# Generated by FakeRAM 2.0
VERSION 5.7 ;
BUSBITCHARS "[]" ;
PROPERTYDEFINITIONS
  MACRO width INTEGER ;
  MACRO depth INTEGER ;
  MACRO banks INTEGER ;
END PROPERTYDEFINITIONS
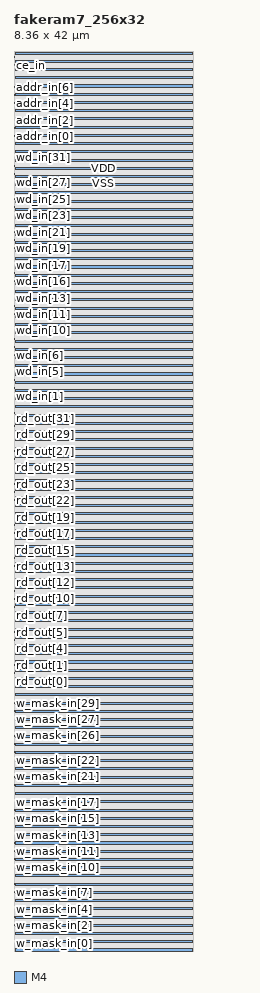
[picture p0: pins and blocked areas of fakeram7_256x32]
MACRO fakeram7_256x32
  PROPERTY width 32 ;
  PROPERTY depth 256 ;
  PROPERTY banks 2 ;
  FOREIGN fakeram7_256x32 0 0 ;
  SYMMETRY X Y R90 ;
  SIZE 8.360 BY 42.000 ;
  CLASS BLOCK ;
  PIN w_mask_in[0]
    DIRECTION INPUT ;
    USE SIGNAL ;
    SHAPE ABUTMENT ;
    PORT
      LAYER M4 ;
      RECT 0.000 0.048 0.024 0.072 ;
    END
  END w_mask_in[0]
  PIN w_mask_in[1]
    DIRECTION INPUT ;
    USE SIGNAL ;
    SHAPE ABUTMENT ;
    PORT
      LAYER M4 ;
      RECT 0.000 0.432 0.024 0.456 ;
    END
  END w_mask_in[1]
  PIN w_mask_in[2]
    DIRECTION INPUT ;
    USE SIGNAL ;
    SHAPE ABUTMENT ;
    PORT
      LAYER M4 ;
      RECT 0.000 0.816 0.024 0.840 ;
    END
  END w_mask_in[2]
  PIN w_mask_in[3]
    DIRECTION INPUT ;
    USE SIGNAL ;
    SHAPE ABUTMENT ;
    PORT
      LAYER M4 ;
      RECT 0.000 1.200 0.024 1.224 ;
    END
  END w_mask_in[3]
  PIN w_mask_in[4]
    DIRECTION INPUT ;
    USE SIGNAL ;
    SHAPE ABUTMENT ;
    PORT
      LAYER M4 ;
      RECT 0.000 1.584 0.024 1.608 ;
    END
  END w_mask_in[4]
  PIN w_mask_in[5]
    DIRECTION INPUT ;
    USE SIGNAL ;
    SHAPE ABUTMENT ;
    PORT
      LAYER M4 ;
      RECT 0.000 1.968 0.024 1.992 ;
    END
  END w_mask_in[5]
  PIN w_mask_in[6]
    DIRECTION INPUT ;
    USE SIGNAL ;
    SHAPE ABUTMENT ;
    PORT
      LAYER M4 ;
      RECT 0.000 2.352 0.024 2.376 ;
    END
  END w_mask_in[6]
  PIN w_mask_in[7]
    DIRECTION INPUT ;
    USE SIGNAL ;
    SHAPE ABUTMENT ;
    PORT
      LAYER M4 ;
      RECT 0.000 2.736 0.024 2.760 ;
    END
  END w_mask_in[7]
  PIN w_mask_in[8]
    DIRECTION INPUT ;
    USE SIGNAL ;
    SHAPE ABUTMENT ;
    PORT
      LAYER M4 ;
      RECT 0.000 3.120 0.024 3.144 ;
    END
  END w_mask_in[8]
  PIN w_mask_in[9]
    DIRECTION INPUT ;
    USE SIGNAL ;
    SHAPE ABUTMENT ;
    PORT
      LAYER M4 ;
      RECT 0.000 3.504 0.024 3.528 ;
    END
  END w_mask_in[9]
  PIN w_mask_in[10]
    DIRECTION INPUT ;
    USE SIGNAL ;
    SHAPE ABUTMENT ;
    PORT
      LAYER M4 ;
      RECT 0.000 3.888 0.024 3.912 ;
    END
  END w_mask_in[10]
  PIN w_mask_in[11]
    DIRECTION INPUT ;
    USE SIGNAL ;
    SHAPE ABUTMENT ;
    PORT
      LAYER M4 ;
      RECT 0.000 4.272 0.024 4.296 ;
    END
  END w_mask_in[11]
  PIN w_mask_in[12]
    DIRECTION INPUT ;
    USE SIGNAL ;
    SHAPE ABUTMENT ;
    PORT
      LAYER M4 ;
      RECT 0.000 4.656 0.024 4.680 ;
    END
  END w_mask_in[12]
  PIN w_mask_in[13]
    DIRECTION INPUT ;
    USE SIGNAL ;
    SHAPE ABUTMENT ;
    PORT
      LAYER M4 ;
      RECT 0.000 5.040 0.024 5.064 ;
    END
  END w_mask_in[13]
  PIN w_mask_in[14]
    DIRECTION INPUT ;
    USE SIGNAL ;
    SHAPE ABUTMENT ;
    PORT
      LAYER M4 ;
      RECT 0.000 5.424 0.024 5.448 ;
    END
  END w_mask_in[14]
  PIN w_mask_in[15]
    DIRECTION INPUT ;
    USE SIGNAL ;
    SHAPE ABUTMENT ;
    PORT
      LAYER M4 ;
      RECT 0.000 5.808 0.024 5.832 ;
    END
  END w_mask_in[15]
  PIN w_mask_in[16]
    DIRECTION INPUT ;
    USE SIGNAL ;
    SHAPE ABUTMENT ;
    PORT
      LAYER M4 ;
      RECT 0.000 6.192 0.024 6.216 ;
    END
  END w_mask_in[16]
  PIN w_mask_in[17]
    DIRECTION INPUT ;
    USE SIGNAL ;
    SHAPE ABUTMENT ;
    PORT
      LAYER M4 ;
      RECT 0.000 6.576 0.024 6.600 ;
    END
  END w_mask_in[17]
  PIN w_mask_in[18]
    DIRECTION INPUT ;
    USE SIGNAL ;
    SHAPE ABUTMENT ;
    PORT
      LAYER M4 ;
      RECT 0.000 6.960 0.024 6.984 ;
    END
  END w_mask_in[18]
  PIN w_mask_in[19]
    DIRECTION INPUT ;
    USE SIGNAL ;
    SHAPE ABUTMENT ;
    PORT
      LAYER M4 ;
      RECT 0.000 7.344 0.024 7.368 ;
    END
  END w_mask_in[19]
  PIN w_mask_in[20]
    DIRECTION INPUT ;
    USE SIGNAL ;
    SHAPE ABUTMENT ;
    PORT
      LAYER M4 ;
      RECT 0.000 7.728 0.024 7.752 ;
    END
  END w_mask_in[20]
  PIN w_mask_in[21]
    DIRECTION INPUT ;
    USE SIGNAL ;
    SHAPE ABUTMENT ;
    PORT
      LAYER M4 ;
      RECT 0.000 8.112 0.024 8.136 ;
    END
  END w_mask_in[21]
  PIN w_mask_in[22]
    DIRECTION INPUT ;
    USE SIGNAL ;
    SHAPE ABUTMENT ;
    PORT
      LAYER M4 ;
      RECT 0.000 8.496 0.024 8.520 ;
    END
  END w_mask_in[22]
  PIN w_mask_in[23]
    DIRECTION INPUT ;
    USE SIGNAL ;
    SHAPE ABUTMENT ;
    PORT
      LAYER M4 ;
      RECT 0.000 8.880 0.024 8.904 ;
    END
  END w_mask_in[23]
  PIN w_mask_in[24]
    DIRECTION INPUT ;
    USE SIGNAL ;
    SHAPE ABUTMENT ;
    PORT
      LAYER M4 ;
      RECT 0.000 9.264 0.024 9.288 ;
    END
  END w_mask_in[24]
  PIN w_mask_in[25]
    DIRECTION INPUT ;
    USE SIGNAL ;
    SHAPE ABUTMENT ;
    PORT
      LAYER M4 ;
      RECT 0.000 9.648 0.024 9.672 ;
    END
  END w_mask_in[25]
  PIN w_mask_in[26]
    DIRECTION INPUT ;
    USE SIGNAL ;
    SHAPE ABUTMENT ;
    PORT
      LAYER M4 ;
      RECT 0.000 10.032 0.024 10.056 ;
    END
  END w_mask_in[26]
  PIN w_mask_in[27]
    DIRECTION INPUT ;
    USE SIGNAL ;
    SHAPE ABUTMENT ;
    PORT
      LAYER M4 ;
      RECT 0.000 10.416 0.024 10.440 ;
    END
  END w_mask_in[27]
  PIN w_mask_in[28]
    DIRECTION INPUT ;
    USE SIGNAL ;
    SHAPE ABUTMENT ;
    PORT
      LAYER M4 ;
      RECT 0.000 10.800 0.024 10.824 ;
    END
  END w_mask_in[28]
  PIN w_mask_in[29]
    DIRECTION INPUT ;
    USE SIGNAL ;
    SHAPE ABUTMENT ;
    PORT
      LAYER M4 ;
      RECT 0.000 11.184 0.024 11.208 ;
    END
  END w_mask_in[29]
  PIN w_mask_in[30]
    DIRECTION INPUT ;
    USE SIGNAL ;
    SHAPE ABUTMENT ;
    PORT
      LAYER M4 ;
      RECT 0.000 11.568 0.024 11.592 ;
    END
  END w_mask_in[30]
  PIN w_mask_in[31]
    DIRECTION INPUT ;
    USE SIGNAL ;
    SHAPE ABUTMENT ;
    PORT
      LAYER M4 ;
      RECT 0.000 11.952 0.024 11.976 ;
    END
  END w_mask_in[31]
  PIN rd_out[0]
    DIRECTION OUTPUT ;
    USE SIGNAL ;
    SHAPE ABUTMENT ;
    PORT
      LAYER M4 ;
      RECT 0.000 12.576 0.024 12.600 ;
    END
  END rd_out[0]
  PIN rd_out[1]
    DIRECTION OUTPUT ;
    USE SIGNAL ;
    SHAPE ABUTMENT ;
    PORT
      LAYER M4 ;
      RECT 0.000 12.960 0.024 12.984 ;
    END
  END rd_out[1]
  PIN rd_out[2]
    DIRECTION OUTPUT ;
    USE SIGNAL ;
    SHAPE ABUTMENT ;
    PORT
      LAYER M4 ;
      RECT 0.000 13.344 0.024 13.368 ;
    END
  END rd_out[2]
  PIN rd_out[3]
    DIRECTION OUTPUT ;
    USE SIGNAL ;
    SHAPE ABUTMENT ;
    PORT
      LAYER M4 ;
      RECT 0.000 13.728 0.024 13.752 ;
    END
  END rd_out[3]
  PIN rd_out[4]
    DIRECTION OUTPUT ;
    USE SIGNAL ;
    SHAPE ABUTMENT ;
    PORT
      LAYER M4 ;
      RECT 0.000 14.112 0.024 14.136 ;
    END
  END rd_out[4]
  PIN rd_out[5]
    DIRECTION OUTPUT ;
    USE SIGNAL ;
    SHAPE ABUTMENT ;
    PORT
      LAYER M4 ;
      RECT 0.000 14.496 0.024 14.520 ;
    END
  END rd_out[5]
  PIN rd_out[6]
    DIRECTION OUTPUT ;
    USE SIGNAL ;
    SHAPE ABUTMENT ;
    PORT
      LAYER M4 ;
      RECT 0.000 14.880 0.024 14.904 ;
    END
  END rd_out[6]
  PIN rd_out[7]
    DIRECTION OUTPUT ;
    USE SIGNAL ;
    SHAPE ABUTMENT ;
    PORT
      LAYER M4 ;
      RECT 0.000 15.264 0.024 15.288 ;
    END
  END rd_out[7]
  PIN rd_out[8]
    DIRECTION OUTPUT ;
    USE SIGNAL ;
    SHAPE ABUTMENT ;
    PORT
      LAYER M4 ;
      RECT 0.000 15.648 0.024 15.672 ;
    END
  END rd_out[8]
  PIN rd_out[9]
    DIRECTION OUTPUT ;
    USE SIGNAL ;
    SHAPE ABUTMENT ;
    PORT
      LAYER M4 ;
      RECT 0.000 16.032 0.024 16.056 ;
    END
  END rd_out[9]
  PIN rd_out[10]
    DIRECTION OUTPUT ;
    USE SIGNAL ;
    SHAPE ABUTMENT ;
    PORT
      LAYER M4 ;
      RECT 0.000 16.416 0.024 16.440 ;
    END
  END rd_out[10]
  PIN rd_out[11]
    DIRECTION OUTPUT ;
    USE SIGNAL ;
    SHAPE ABUTMENT ;
    PORT
      LAYER M4 ;
      RECT 0.000 16.800 0.024 16.824 ;
    END
  END rd_out[11]
  PIN rd_out[12]
    DIRECTION OUTPUT ;
    USE SIGNAL ;
    SHAPE ABUTMENT ;
    PORT
      LAYER M4 ;
      RECT 0.000 17.184 0.024 17.208 ;
    END
  END rd_out[12]
  PIN rd_out[13]
    DIRECTION OUTPUT ;
    USE SIGNAL ;
    SHAPE ABUTMENT ;
    PORT
      LAYER M4 ;
      RECT 0.000 17.568 0.024 17.592 ;
    END
  END rd_out[13]
  PIN rd_out[14]
    DIRECTION OUTPUT ;
    USE SIGNAL ;
    SHAPE ABUTMENT ;
    PORT
      LAYER M4 ;
      RECT 0.000 17.952 0.024 17.976 ;
    END
  END rd_out[14]
  PIN rd_out[15]
    DIRECTION OUTPUT ;
    USE SIGNAL ;
    SHAPE ABUTMENT ;
    PORT
      LAYER M4 ;
      RECT 0.000 18.336 0.024 18.360 ;
    END
  END rd_out[15]
  PIN rd_out[16]
    DIRECTION OUTPUT ;
    USE SIGNAL ;
    SHAPE ABUTMENT ;
    PORT
      LAYER M4 ;
      RECT 0.000 18.720 0.024 18.744 ;
    END
  END rd_out[16]
  PIN rd_out[17]
    DIRECTION OUTPUT ;
    USE SIGNAL ;
    SHAPE ABUTMENT ;
    PORT
      LAYER M4 ;
      RECT 0.000 19.104 0.024 19.128 ;
    END
  END rd_out[17]
  PIN rd_out[18]
    DIRECTION OUTPUT ;
    USE SIGNAL ;
    SHAPE ABUTMENT ;
    PORT
      LAYER M4 ;
      RECT 0.000 19.488 0.024 19.512 ;
    END
  END rd_out[18]
  PIN rd_out[19]
    DIRECTION OUTPUT ;
    USE SIGNAL ;
    SHAPE ABUTMENT ;
    PORT
      LAYER M4 ;
      RECT 0.000 19.872 0.024 19.896 ;
    END
  END rd_out[19]
  PIN rd_out[20]
    DIRECTION OUTPUT ;
    USE SIGNAL ;
    SHAPE ABUTMENT ;
    PORT
      LAYER M4 ;
      RECT 0.000 20.256 0.024 20.280 ;
    END
  END rd_out[20]
  PIN rd_out[21]
    DIRECTION OUTPUT ;
    USE SIGNAL ;
    SHAPE ABUTMENT ;
    PORT
      LAYER M4 ;
      RECT 0.000 20.640 0.024 20.664 ;
    END
  END rd_out[21]
  PIN rd_out[22]
    DIRECTION OUTPUT ;
    USE SIGNAL ;
    SHAPE ABUTMENT ;
    PORT
      LAYER M4 ;
      RECT 0.000 21.024 0.024 21.048 ;
    END
  END rd_out[22]
  PIN rd_out[23]
    DIRECTION OUTPUT ;
    USE SIGNAL ;
    SHAPE ABUTMENT ;
    PORT
      LAYER M4 ;
      RECT 0.000 21.408 0.024 21.432 ;
    END
  END rd_out[23]
  PIN rd_out[24]
    DIRECTION OUTPUT ;
    USE SIGNAL ;
    SHAPE ABUTMENT ;
    PORT
      LAYER M4 ;
      RECT 0.000 21.792 0.024 21.816 ;
    END
  END rd_out[24]
  PIN rd_out[25]
    DIRECTION OUTPUT ;
    USE SIGNAL ;
    SHAPE ABUTMENT ;
    PORT
      LAYER M4 ;
      RECT 0.000 22.176 0.024 22.200 ;
    END
  END rd_out[25]
  PIN rd_out[26]
    DIRECTION OUTPUT ;
    USE SIGNAL ;
    SHAPE ABUTMENT ;
    PORT
      LAYER M4 ;
      RECT 0.000 22.560 0.024 22.584 ;
    END
  END rd_out[26]
  PIN rd_out[27]
    DIRECTION OUTPUT ;
    USE SIGNAL ;
    SHAPE ABUTMENT ;
    PORT
      LAYER M4 ;
      RECT 0.000 22.944 0.024 22.968 ;
    END
  END rd_out[27]
  PIN rd_out[28]
    DIRECTION OUTPUT ;
    USE SIGNAL ;
    SHAPE ABUTMENT ;
    PORT
      LAYER M4 ;
      RECT 0.000 23.328 0.024 23.352 ;
    END
  END rd_out[28]
  PIN rd_out[29]
    DIRECTION OUTPUT ;
    USE SIGNAL ;
    SHAPE ABUTMENT ;
    PORT
      LAYER M4 ;
      RECT 0.000 23.712 0.024 23.736 ;
    END
  END rd_out[29]
  PIN rd_out[30]
    DIRECTION OUTPUT ;
    USE SIGNAL ;
    SHAPE ABUTMENT ;
    PORT
      LAYER M4 ;
      RECT 0.000 24.096 0.024 24.120 ;
    END
  END rd_out[30]
  PIN rd_out[31]
    DIRECTION OUTPUT ;
    USE SIGNAL ;
    SHAPE ABUTMENT ;
    PORT
      LAYER M4 ;
      RECT 0.000 24.480 0.024 24.504 ;
    END
  END rd_out[31]
  PIN wd_in[0]
    DIRECTION INPUT ;
    USE SIGNAL ;
    SHAPE ABUTMENT ;
    PORT
      LAYER M4 ;
      RECT 0.000 25.104 0.024 25.128 ;
    END
  END wd_in[0]
  PIN wd_in[1]
    DIRECTION INPUT ;
    USE SIGNAL ;
    SHAPE ABUTMENT ;
    PORT
      LAYER M4 ;
      RECT 0.000 25.488 0.024 25.512 ;
    END
  END wd_in[1]
  PIN wd_in[2]
    DIRECTION INPUT ;
    USE SIGNAL ;
    SHAPE ABUTMENT ;
    PORT
      LAYER M4 ;
      RECT 0.000 25.872 0.024 25.896 ;
    END
  END wd_in[2]
  PIN wd_in[3]
    DIRECTION INPUT ;
    USE SIGNAL ;
    SHAPE ABUTMENT ;
    PORT
      LAYER M4 ;
      RECT 0.000 26.256 0.024 26.280 ;
    END
  END wd_in[3]
  PIN wd_in[4]
    DIRECTION INPUT ;
    USE SIGNAL ;
    SHAPE ABUTMENT ;
    PORT
      LAYER M4 ;
      RECT 0.000 26.640 0.024 26.664 ;
    END
  END wd_in[4]
  PIN wd_in[5]
    DIRECTION INPUT ;
    USE SIGNAL ;
    SHAPE ABUTMENT ;
    PORT
      LAYER M4 ;
      RECT 0.000 27.024 0.024 27.048 ;
    END
  END wd_in[5]
  PIN wd_in[6]
    DIRECTION INPUT ;
    USE SIGNAL ;
    SHAPE ABUTMENT ;
    PORT
      LAYER M4 ;
      RECT 0.000 27.408 0.024 27.432 ;
    END
  END wd_in[6]
  PIN wd_in[7]
    DIRECTION INPUT ;
    USE SIGNAL ;
    SHAPE ABUTMENT ;
    PORT
      LAYER M4 ;
      RECT 0.000 27.792 0.024 27.816 ;
    END
  END wd_in[7]
  PIN wd_in[8]
    DIRECTION INPUT ;
    USE SIGNAL ;
    SHAPE ABUTMENT ;
    PORT
      LAYER M4 ;
      RECT 0.000 28.176 0.024 28.200 ;
    END
  END wd_in[8]
  PIN wd_in[9]
    DIRECTION INPUT ;
    USE SIGNAL ;
    SHAPE ABUTMENT ;
    PORT
      LAYER M4 ;
      RECT 0.000 28.560 0.024 28.584 ;
    END
  END wd_in[9]
  PIN wd_in[10]
    DIRECTION INPUT ;
    USE SIGNAL ;
    SHAPE ABUTMENT ;
    PORT
      LAYER M4 ;
      RECT 0.000 28.944 0.024 28.968 ;
    END
  END wd_in[10]
  PIN wd_in[11]
    DIRECTION INPUT ;
    USE SIGNAL ;
    SHAPE ABUTMENT ;
    PORT
      LAYER M4 ;
      RECT 0.000 29.328 0.024 29.352 ;
    END
  END wd_in[11]
  PIN wd_in[12]
    DIRECTION INPUT ;
    USE SIGNAL ;
    SHAPE ABUTMENT ;
    PORT
      LAYER M4 ;
      RECT 0.000 29.712 0.024 29.736 ;
    END
  END wd_in[12]
  PIN wd_in[13]
    DIRECTION INPUT ;
    USE SIGNAL ;
    SHAPE ABUTMENT ;
    PORT
      LAYER M4 ;
      RECT 0.000 30.096 0.024 30.120 ;
    END
  END wd_in[13]
  PIN wd_in[14]
    DIRECTION INPUT ;
    USE SIGNAL ;
    SHAPE ABUTMENT ;
    PORT
      LAYER M4 ;
      RECT 0.000 30.480 0.024 30.504 ;
    END
  END wd_in[14]
  PIN wd_in[15]
    DIRECTION INPUT ;
    USE SIGNAL ;
    SHAPE ABUTMENT ;
    PORT
      LAYER M4 ;
      RECT 0.000 30.864 0.024 30.888 ;
    END
  END wd_in[15]
  PIN wd_in[16]
    DIRECTION INPUT ;
    USE SIGNAL ;
    SHAPE ABUTMENT ;
    PORT
      LAYER M4 ;
      RECT 0.000 31.248 0.024 31.272 ;
    END
  END wd_in[16]
  PIN wd_in[17]
    DIRECTION INPUT ;
    USE SIGNAL ;
    SHAPE ABUTMENT ;
    PORT
      LAYER M4 ;
      RECT 0.000 31.632 0.024 31.656 ;
    END
  END wd_in[17]
  PIN wd_in[18]
    DIRECTION INPUT ;
    USE SIGNAL ;
    SHAPE ABUTMENT ;
    PORT
      LAYER M4 ;
      RECT 0.000 32.016 0.024 32.040 ;
    END
  END wd_in[18]
  PIN wd_in[19]
    DIRECTION INPUT ;
    USE SIGNAL ;
    SHAPE ABUTMENT ;
    PORT
      LAYER M4 ;
      RECT 0.000 32.400 0.024 32.424 ;
    END
  END wd_in[19]
  PIN wd_in[20]
    DIRECTION INPUT ;
    USE SIGNAL ;
    SHAPE ABUTMENT ;
    PORT
      LAYER M4 ;
      RECT 0.000 32.784 0.024 32.808 ;
    END
  END wd_in[20]
  PIN wd_in[21]
    DIRECTION INPUT ;
    USE SIGNAL ;
    SHAPE ABUTMENT ;
    PORT
      LAYER M4 ;
      RECT 0.000 33.168 0.024 33.192 ;
    END
  END wd_in[21]
  PIN wd_in[22]
    DIRECTION INPUT ;
    USE SIGNAL ;
    SHAPE ABUTMENT ;
    PORT
      LAYER M4 ;
      RECT 0.000 33.552 0.024 33.576 ;
    END
  END wd_in[22]
  PIN wd_in[23]
    DIRECTION INPUT ;
    USE SIGNAL ;
    SHAPE ABUTMENT ;
    PORT
      LAYER M4 ;
      RECT 0.000 33.936 0.024 33.960 ;
    END
  END wd_in[23]
  PIN wd_in[24]
    DIRECTION INPUT ;
    USE SIGNAL ;
    SHAPE ABUTMENT ;
    PORT
      LAYER M4 ;
      RECT 0.000 34.320 0.024 34.344 ;
    END
  END wd_in[24]
  PIN wd_in[25]
    DIRECTION INPUT ;
    USE SIGNAL ;
    SHAPE ABUTMENT ;
    PORT
      LAYER M4 ;
      RECT 0.000 34.704 0.024 34.728 ;
    END
  END wd_in[25]
  PIN wd_in[26]
    DIRECTION INPUT ;
    USE SIGNAL ;
    SHAPE ABUTMENT ;
    PORT
      LAYER M4 ;
      RECT 0.000 35.088 0.024 35.112 ;
    END
  END wd_in[26]
  PIN wd_in[27]
    DIRECTION INPUT ;
    USE SIGNAL ;
    SHAPE ABUTMENT ;
    PORT
      LAYER M4 ;
      RECT 0.000 35.472 0.024 35.496 ;
    END
  END wd_in[27]
  PIN wd_in[28]
    DIRECTION INPUT ;
    USE SIGNAL ;
    SHAPE ABUTMENT ;
    PORT
      LAYER M4 ;
      RECT 0.000 35.856 0.024 35.880 ;
    END
  END wd_in[28]
  PIN wd_in[29]
    DIRECTION INPUT ;
    USE SIGNAL ;
    SHAPE ABUTMENT ;
    PORT
      LAYER M4 ;
      RECT 0.000 36.240 0.024 36.264 ;
    END
  END wd_in[29]
  PIN wd_in[30]
    DIRECTION INPUT ;
    USE SIGNAL ;
    SHAPE ABUTMENT ;
    PORT
      LAYER M4 ;
      RECT 0.000 36.624 0.024 36.648 ;
    END
  END wd_in[30]
  PIN wd_in[31]
    DIRECTION INPUT ;
    USE SIGNAL ;
    SHAPE ABUTMENT ;
    PORT
      LAYER M4 ;
      RECT 0.000 37.008 0.024 37.032 ;
    END
  END wd_in[31]
  PIN addr_in[0]
    DIRECTION INPUT ;
    USE SIGNAL ;
    SHAPE ABUTMENT ;
    PORT
      LAYER M4 ;
      RECT 0.000 37.632 0.024 37.656 ;
    END
  END addr_in[0]
  PIN addr_in[1]
    DIRECTION INPUT ;
    USE SIGNAL ;
    SHAPE ABUTMENT ;
    PORT
      LAYER M4 ;
      RECT 0.000 38.016 0.024 38.040 ;
    END
  END addr_in[1]
  PIN addr_in[2]
    DIRECTION INPUT ;
    USE SIGNAL ;
    SHAPE ABUTMENT ;
    PORT
      LAYER M4 ;
      RECT 0.000 38.400 0.024 38.424 ;
    END
  END addr_in[2]
  PIN addr_in[3]
    DIRECTION INPUT ;
    USE SIGNAL ;
    SHAPE ABUTMENT ;
    PORT
      LAYER M4 ;
      RECT 0.000 38.784 0.024 38.808 ;
    END
  END addr_in[3]
  PIN addr_in[4]
    DIRECTION INPUT ;
    USE SIGNAL ;
    SHAPE ABUTMENT ;
    PORT
      LAYER M4 ;
      RECT 0.000 39.168 0.024 39.192 ;
    END
  END addr_in[4]
  PIN addr_in[5]
    DIRECTION INPUT ;
    USE SIGNAL ;
    SHAPE ABUTMENT ;
    PORT
      LAYER M4 ;
      RECT 0.000 39.552 0.024 39.576 ;
    END
  END addr_in[5]
  PIN addr_in[6]
    DIRECTION INPUT ;
    USE SIGNAL ;
    SHAPE ABUTMENT ;
    PORT
      LAYER M4 ;
      RECT 0.000 39.936 0.024 39.960 ;
    END
  END addr_in[6]
  PIN addr_in[7]
    DIRECTION INPUT ;
    USE SIGNAL ;
    SHAPE ABUTMENT ;
    PORT
      LAYER M4 ;
      RECT 0.000 40.320 0.024 40.344 ;
    END
  END addr_in[7]
  PIN we_in
    DIRECTION INPUT ;
    USE SIGNAL ;
    SHAPE ABUTMENT ;
    PORT
      LAYER M4 ;
      RECT 0.000 40.944 0.024 40.968 ;
    END
  END we_in
  PIN ce_in
    DIRECTION INPUT ;
    USE SIGNAL ;
    SHAPE ABUTMENT ;
    PORT
      LAYER M4 ;
      RECT 0.000 41.328 0.024 41.352 ;
    END
  END ce_in
  PIN clk
    DIRECTION INPUT ;
    USE SIGNAL ;
    SHAPE ABUTMENT ;
    PORT
      LAYER M4 ;
      RECT 0.000 41.712 0.024 41.736 ;
    END
  END clk
  PIN VSS
    DIRECTION INOUT ;
    USE GROUND ;
    PORT
      LAYER M4 ;
      RECT 0.048 0.000 8.312 0.096 ;
      RECT 0.048 0.768 8.312 0.864 ;
      RECT 0.048 1.536 8.312 1.632 ;
      RECT 0.048 2.304 8.312 2.400 ;
      RECT 0.048 3.072 8.312 3.168 ;
      RECT 0.048 3.840 8.312 3.936 ;
      RECT 0.048 4.608 8.312 4.704 ;
      RECT 0.048 5.376 8.312 5.472 ;
      RECT 0.048 6.144 8.312 6.240 ;
      RECT 0.048 6.912 8.312 7.008 ;
      RECT 0.048 7.680 8.312 7.776 ;
      RECT 0.048 8.448 8.312 8.544 ;
      RECT 0.048 9.216 8.312 9.312 ;
      RECT 0.048 9.984 8.312 10.080 ;
      RECT 0.048 10.752 8.312 10.848 ;
      RECT 0.048 11.520 8.312 11.616 ;
      RECT 0.048 12.288 8.312 12.384 ;
      RECT 0.048 13.056 8.312 13.152 ;
      RECT 0.048 13.824 8.312 13.920 ;
      RECT 0.048 14.592 8.312 14.688 ;
      RECT 0.048 15.360 8.312 15.456 ;
      RECT 0.048 16.128 8.312 16.224 ;
      RECT 0.048 16.896 8.312 16.992 ;
      RECT 0.048 17.664 8.312 17.760 ;
      RECT 0.048 18.432 8.312 18.528 ;
      RECT 0.048 19.200 8.312 19.296 ;
      RECT 0.048 19.968 8.312 20.064 ;
      RECT 0.048 20.736 8.312 20.832 ;
      RECT 0.048 21.504 8.312 21.600 ;
      RECT 0.048 22.272 8.312 22.368 ;
      RECT 0.048 23.040 8.312 23.136 ;
      RECT 0.048 23.808 8.312 23.904 ;
      RECT 0.048 24.576 8.312 24.672 ;
      RECT 0.048 25.344 8.312 25.440 ;
      RECT 0.048 26.112 8.312 26.208 ;
      RECT 0.048 26.880 8.312 26.976 ;
      RECT 0.048 27.648 8.312 27.744 ;
      RECT 0.048 28.416 8.312 28.512 ;
      RECT 0.048 29.184 8.312 29.280 ;
      RECT 0.048 29.952 8.312 30.048 ;
      RECT 0.048 30.720 8.312 30.816 ;
      RECT 0.048 31.488 8.312 31.584 ;
      RECT 0.048 32.256 8.312 32.352 ;
      RECT 0.048 33.024 8.312 33.120 ;
      RECT 0.048 33.792 8.312 33.888 ;
      RECT 0.048 34.560 8.312 34.656 ;
      RECT 0.048 35.328 8.312 35.424 ;
      RECT 0.048 36.096 8.312 36.192 ;
      RECT 0.048 36.864 8.312 36.960 ;
      RECT 0.048 37.632 8.312 37.728 ;
      RECT 0.048 38.400 8.312 38.496 ;
      RECT 0.048 39.168 8.312 39.264 ;
      RECT 0.048 39.936 8.312 40.032 ;
      RECT 0.048 40.704 8.312 40.800 ;
      RECT 0.048 41.472 8.312 41.568 ;
    END
  END VSS
  PIN VDD
    DIRECTION INOUT ;
    USE POWER ;
    PORT
      LAYER M4 ;
      RECT 0.048 0.384 8.312 0.480 ;
      RECT 0.048 1.152 8.312 1.248 ;
      RECT 0.048 1.920 8.312 2.016 ;
      RECT 0.048 2.688 8.312 2.784 ;
      RECT 0.048 3.456 8.312 3.552 ;
      RECT 0.048 4.224 8.312 4.320 ;
      RECT 0.048 4.992 8.312 5.088 ;
      RECT 0.048 5.760 8.312 5.856 ;
      RECT 0.048 6.528 8.312 6.624 ;
      RECT 0.048 7.296 8.312 7.392 ;
      RECT 0.048 8.064 8.312 8.160 ;
      RECT 0.048 8.832 8.312 8.928 ;
      RECT 0.048 9.600 8.312 9.696 ;
      RECT 0.048 10.368 8.312 10.464 ;
      RECT 0.048 11.136 8.312 11.232 ;
      RECT 0.048 11.904 8.312 12.000 ;
      RECT 0.048 12.672 8.312 12.768 ;
      RECT 0.048 13.440 8.312 13.536 ;
      RECT 0.048 14.208 8.312 14.304 ;
      RECT 0.048 14.976 8.312 15.072 ;
      RECT 0.048 15.744 8.312 15.840 ;
      RECT 0.048 16.512 8.312 16.608 ;
      RECT 0.048 17.280 8.312 17.376 ;
      RECT 0.048 18.048 8.312 18.144 ;
      RECT 0.048 18.816 8.312 18.912 ;
      RECT 0.048 19.584 8.312 19.680 ;
      RECT 0.048 20.352 8.312 20.448 ;
      RECT 0.048 21.120 8.312 21.216 ;
      RECT 0.048 21.888 8.312 21.984 ;
      RECT 0.048 22.656 8.312 22.752 ;
      RECT 0.048 23.424 8.312 23.520 ;
      RECT 0.048 24.192 8.312 24.288 ;
      RECT 0.048 24.960 8.312 25.056 ;
      RECT 0.048 25.728 8.312 25.824 ;
      RECT 0.048 26.496 8.312 26.592 ;
      RECT 0.048 27.264 8.312 27.360 ;
      RECT 0.048 28.032 8.312 28.128 ;
      RECT 0.048 28.800 8.312 28.896 ;
      RECT 0.048 29.568 8.312 29.664 ;
      RECT 0.048 30.336 8.312 30.432 ;
      RECT 0.048 31.104 8.312 31.200 ;
      RECT 0.048 31.872 8.312 31.968 ;
      RECT 0.048 32.640 8.312 32.736 ;
      RECT 0.048 33.408 8.312 33.504 ;
      RECT 0.048 34.176 8.312 34.272 ;
      RECT 0.048 34.944 8.312 35.040 ;
      RECT 0.048 35.712 8.312 35.808 ;
      RECT 0.048 36.480 8.312 36.576 ;
      RECT 0.048 37.248 8.312 37.344 ;
      RECT 0.048 38.016 8.312 38.112 ;
      RECT 0.048 38.784 8.312 38.880 ;
      RECT 0.048 39.552 8.312 39.648 ;
      RECT 0.048 40.320 8.312 40.416 ;
      RECT 0.048 41.088 8.312 41.184 ;
      RECT 0.048 41.856 8.312 41.952 ;
    END
  END VDD
  OBS
    LAYER M1 ;
    RECT 0 0 8.360 42.000 ;
    LAYER M2 ;
    RECT 0 0 8.360 42.000 ;
    LAYER M3 ;
    RECT 0 0 8.360 42.000 ;
    LAYER M4 ;
    RECT 0 0 8.360 42.000 ;
  END
END fakeram7_256x32

END LIBRARY
